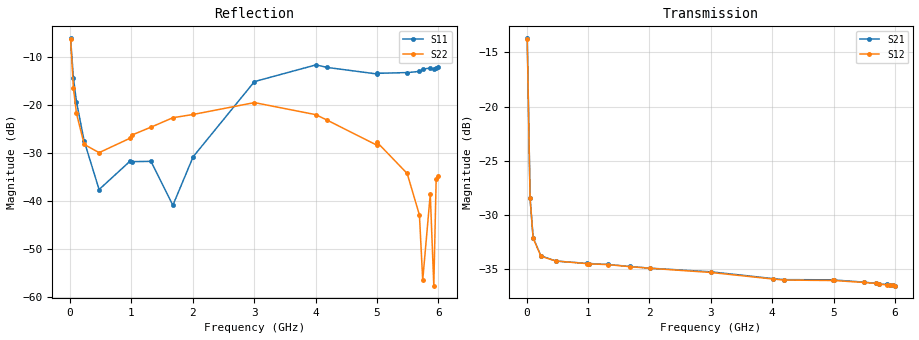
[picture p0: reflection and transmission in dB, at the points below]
!Agilent Technologies,E5071C,MY46316741,A.11.02
!Date: Tue Oct 20 14:45:49 2020
!Data & Calibration Information:
!Freq	S11:SOLT4(ON)	S21:SOLT4(ON)	S12:SOLT4(ON)	S22:SOLT4(ON)
!PortZ  Port1:50+j0  Port2:50+j0
!Above PortZ is port z conversion or system Z0 setting when saving the data.
!When reading, reference impedance value at option line is always used.
# Hz S dB R 50
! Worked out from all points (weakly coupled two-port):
!   1561 points, 10 MHz to 6 GHz, reference 50 ohm
!   highest |S21| = -13.70 dB at 10 MHz (marker M1); lowest = -36.5 dB at 6 GHz (marker M2)
!   lowest |S11| = -40.9 dB at 1.676 GHz (marker M3), VSWR 1.02, Z = 49.1 - j0.0486 ohm
!   |S11| at or under -10 dB: 27.52 MHz to end of sweep
!   |S22| runs from -67.0 to -6.1 dB; largest |S21 - S12| = 0.0023
!   S11 on the Smith chart (normalised r, x): 10 MHz: 1.90, -1.30; 977.6 MHz: 1.03, -0.04; 4.191 GHz: 0.60, +0.02; 4.994 GHz: 1.12, +0.44; 6 GHz: 0.91, -0.49
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1e7  -6.07 -31.3  -13.70 -51.5  -13.79 -51.2  -6.12 -40.8
5.607692e7  -14.27 -69.0  -28.47 -70.2  -28.49 -70.0  -16.45 -90.5
1.059936e8  -19.31 -81.3  -32.12 -56.7  -32.15 -56.5  -21.73 -111.3
2.327051e8  -27.52 -91.7  -33.79 -53.9  -33.83 -53.8  -28.18 -156.2
4.74609e8  -37.58 -61.7  -34.27 -77.3  -34.27 -77.4  -29.89 133.3
9.776154e8  -31.68 -56.7  -34.49 -142.0  -34.51 -142.1  -26.89 51.6
1.012173e9  -31.77 -55.0  -34.50 -146.7  -34.53 -146.9  -26.20 46.7
1.319353e9  -31.70 -92.5  -34.59 171.7  -34.60 171.4  -24.58 14.4
1.676449e9  -40.86 -176.9  -34.77 123.0  -34.79 122.8  -22.61 -14.5
2.006667e9  -30.75 60.3  -34.93 77.6  -34.94 77.6  -21.93 -43.7
3.005e9  -15.08 -54.4  -35.27 -59.3  -35.33 -59.7  -19.46 -120.1
4.007173e9  -11.60 -163.8  -35.89 163.8  -35.93 163.6  -21.98 163.1
4.191481e9  -12.13 175.5  -35.99 139.2  -36.03 139.1  -23.13 165.5
4.993987e9  -13.48 63.5  -36.01 30.7  -36.07 30.7  -28.30 95.0
5.001667e9  -13.36 62.3  -36.02 29.7  -36.07 29.7  -27.71 94.0
5.493154e9  -13.20 -14.6  -36.22 -36.8  -36.25 -36.7  -34.23 67.6
5.692821e9  -12.96 -43.7  -36.34 -64.2  -36.34 -64.2  -42.88 45.0
5.746577e9  -12.51 -53.9  -36.39 -71.6  -36.41 -71.4  -56.48 -118.1
5.869449e9  -12.23 -70.3  -36.44 -87.7  -36.47 -87.6  -38.53 -115.5
5.927045e9  -12.52 -75.3  -36.48 -95.3  -36.49 -95.3  -57.62 134.9
5.965442e9  -12.25 -83.0  -36.49 -100.4  -36.52 -100.4  -35.45 -160.0
6e9  -12.01 -86.4  -36.54 -105.0  -36.55 -104.8  -34.69 -116.6
